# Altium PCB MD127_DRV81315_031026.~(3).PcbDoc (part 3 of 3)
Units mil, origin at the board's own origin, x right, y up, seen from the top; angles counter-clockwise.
Board outline 4400.04 x 2800.87 mil, 2 copper layers (Top Layer, Bottom Layer), stack 64.712 mil thick; 152 components, 62 nets, 376 pads, 751 vias.

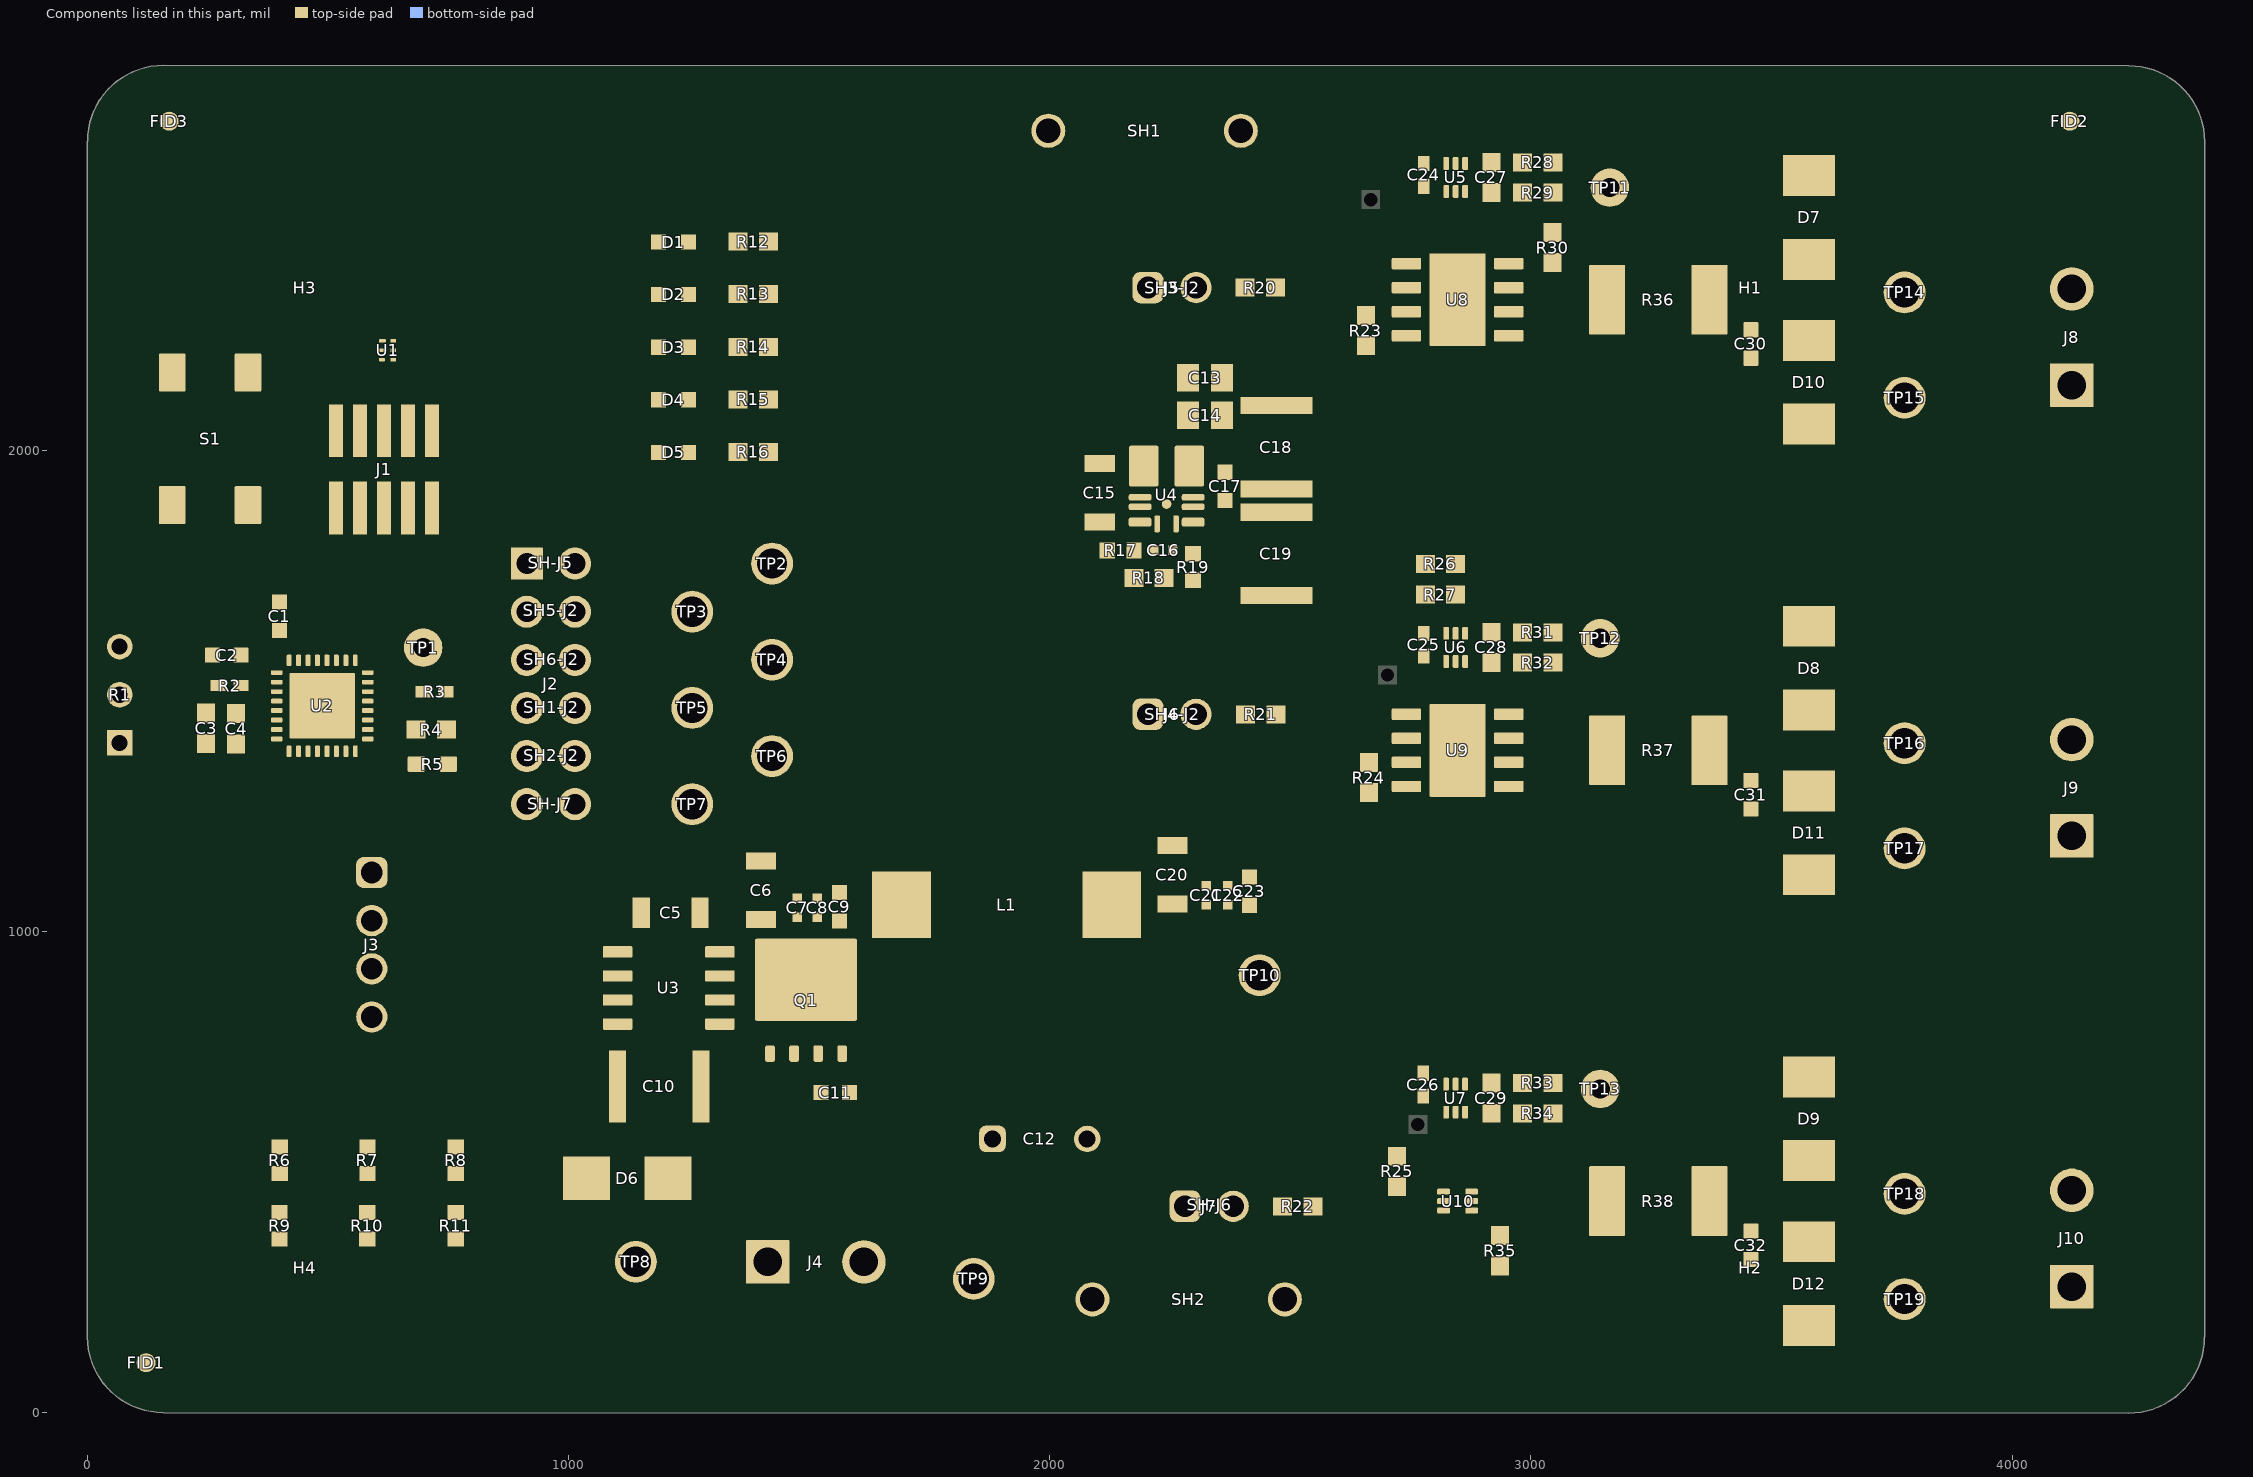
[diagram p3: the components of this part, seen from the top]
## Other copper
Top Layer:
  pour cut-out: 170.11,2634.3 cw(c170.11,2684.08) 120.32,2684.08 cw(c170.11,2684.08) 170.11,2733.87 cw(c170.11,2684.08) 219.9,2684.08 cw(c170.11,2684.08)
  pour cut-out: 122.11,54.3 cw(c122.11,104.08) 72.32,104.08 cw(c122.11,104.08) 122.11,153.87 cw(c122.11,104.08) 171.9,104.08 cw(c122.11,104.08)
  pour cut-out: 4120.11,2634.3 cw(c4120.11,2684.08) 4070.32,2684.08 cw(c4120.11,2684.08) 4120.11,2733.87 cw(c4120.11,2684.08) 4169.9,2684.08 cw(c4120.11,2684.08)
  region net NetU4_5: 2213.61,1895.61 2225.56,1907.57 2225.56,2006.35 2222.26,2009.65 2167.1,2009.65 2161.82,2004.36 2161.82,1900.07 2166.27,1895.61
  region net BUCK_3V3: 191.6,1488.81 191.6,1554.6 198.74,1561.74 225.19,1561.74 245.93,1541 269.57,1541 287.57,1522.99 287.57,1498.14 300.75,1484.96 404.82,1484.96 406.38,1483.4 406.38,1475.17 403.3,1472.09 375.98,1472.09 350.35,1446.47 350.35,1438.98 341.8,1430.43 323.99,1430.43 206.18,1430.43 191.6,1445.01
  region net 3V3: 1209.45,1973.16 1204.5,1968.21 1127.79,1968.21 1116.3,1980 1116.3,2221.3 1136.79,2241.79 1202.26,2241.79 1209.45,2234.6
  region net 3V3: 1200.21,2414.89 1129.11,2414.89 1125,2419 1125,2446 1128.79,2449.79 1200.91,2449.79 1202.26,2448.44 1202.26,2416.95
  region net 3V3: 2774,1603.79 2691.21,1603.79 2665,1630 2665,1705 2687.2,1727.2 2803.8,1727.2 2810.65,1720.35 2810.65,1653.58 2830.75,1633.48 2830.75,1605.74 2828.8,1603.79
  region net SRC_U3: 2993.19,436.65 2909.15,436.65 2894.05,451.76 2863.01,451.78 2860.51,454.29 2860.51,563.15 2868.36,571 2994,571 3017.91,594.91 3017.91,641.31 3034.61,658.01 3074.14,658.01 3094.77,678.63 3094.77,721.77 3112,739 3251,739 3277,713 3277,362.53 3274.14,359.67 3070.16,359.67
  region net BUCK_3V3: 631.06,2223.75 628.36,2226.45 628.36,2242.5 622,2248.86 622,2273 624,2275 643,2275 646.81,2271.19 646.81,2226.47 644.09,2223.75
  region net 3V3: 2769.71,2376.3 2771.71,2378.31 2771.71,2431.29 2766,2437 2713,2437 2708,2432 2708,2380.16 2711.87,2376.3
  region net nRST: 619.54,2218.89 584.68,2218.89 575.2,2209.41 556.98,2209.41 552.49,2213.9 552.49,2231.49 565.59,2244.58 580.44,2244.58 588.92,2236.1 619.48,2236.1 622.01,2233.57 622.01,2221.37
  region net BUCK_3V3: 776.53,530.78 386.49,530.78 371.96,545.32 371.96,585.47 379.85,593.36 771.22,593.36 788,576.58 788,542.24
  region net GND: 555.91,1403.12 553.88,1401.09 421.28,1401.09 420.09,1402.28 420.09,1439.89 407.36,1452.62 382.83,1452.62 380.85,1454.6 380.85,1464.28 381.7,1465.12 416.21,1465.12 420.09,1469 420.09,1535.72 421.28,1536.91 554.72,1536.91 555.91,1535.72
  region net VM: 2514,986.82 2514,868 2474,828 2136,828 2050,914 2050,1110.41 2082,1138.12 2238.88,1138.12 2306.71,1070.29 2430.53,1070.29
  region net BUCK_3V3: 2313.36,2033.58 2212.92,2033.58 2203.75,2042.74 2203.75,2169.99 2218.67,2184.91 2315.95,2184.91 2326.84,2174.02 2326.84,2046.68
  region net PI_IN: 1965,446 1946,427 1636,427 1620,443 1620,779 1603,796 1387,796 1376.88,806.12 1376.88,913.12 1353,937 1264,937 1227.61,973.39 1227.61,1077.61 1237,1087 1332,1087 1369.8,1049.2 1587.2,1049.2 1594,1056 1594,1121.25 1611.75,1139 1825,1139 1965,999
  region net GND: 2268.19,1863.04 2266.27,1864.96 2241.16,1864.96 2235.78,1859.59 2235.78,1832.56 2238.82,1829.53 2266.27,1829.53 2268.19,1831.45
  region net BUCK_3V3: 2239.68,1805.64 2238.99,1804.95 2238.99,1774.57 2218.01,1753.58 2218.01,1704.39 2235.71,1686.69 2305.88,1686.69 2317.24,1698.05 2317.24,1749.58 2315.62,1751.2 2285.72,1751.2 2269.54,1767.37 2269.54,1802.91 2266.81,1805.64
  region net VM_IN: 1490,322 1490,118 1453,81 1069,81 1037,113 1037,365 1144,472 1144,561 1181,598 1181,837.62 1134.62,884 1062,884 1058,888 1058,923 1066,931 1261.11,931 1267.2,924.91 1267.2,847.8 1286,829 1350,829 1358,821 1358,798 1373,783 1528,783 1547,764 1547,383 1491,327
  region net 3V3: 2802.28,426.07 2831.74,426.07 2833.87,423.94 2833.87,383.87 2832,382 2803,382 2801,384 2801,424.78
  region net 3V3: 2765.07,505.65 2774.79,515.36 2774.79,551.21 2765.89,560.11 2710.43,560.11 2701.93,551.61 2701.93,514.21 2710.5,505.65
  region net SRC_U1: 3025.97,2516.84 3025.97,2554.24 3034.47,2562.74 3074.14,2562.74 3116.4,2605 3176,2605 3203.2,2577.8 3203.2,2516.89 3186.26,2499.94 3042.87,2499.94
  region net 3V3: 2675.7,2237.19 2638.3,2237.19 2629.73,2228.62 2629.73,2148.27 2636,2142 2679,2142 2684.2,2147.2 2684.2,2228.69
  region net 3V3: 2807,2649 2748.21,2649 2740,2640.79 2740,2589.63 2749.21,2580.43 2828.8,2580.43 2830.75,2582.38 2830.75,2625.25
  region net OUT_U2: 3071.77,1239.98 3031.73,1280.02 2923.84,1280.02 2911.01,1291.34 2911.01,1479.89 2903.2,1487.7 2787.19,1487.7 2781.29,1481.8 2781.29,1029.71 2811,1000 3480.36,1000 3487.51,1007.15 3487.51,1165.51 3526.99,1204.99 3660.39,1204.99 3749.39,1294 4314,1294 4342.57,1322.57 4342.57,1495.87 4297.4,1541.04 3522.37,1541.04 3487.51,1506.18 3487.51,1300.14 3469.14,1281.77 3241.76,1281.76 3199.98,1239.98
  region net 3V3: 2680.43,1237.43 2690.2,1246.92 2690.2,1299.67 2681.7,1308.17 2644.3,1308.17 2635.73,1299.6 2635.73,1246.66 2644.96,1237.43
  region net 3V3: 2685,711.5 2712.48,684.02 2796.24,684.02 2814.22,667.16 2828.03,667.16 2830.47,669.6 2830.47,717.53 2807,741 2694,741 2685,732
  region net OUT_U3: 2985.97,427.67 3062.64,351 3475.68,351 3483.03,358.34 3483.03,571.54 3517.52,606.02 4303.98,606.02 4342.57,567.43 4342.57,384.57 4316.34,358.34 3757.91,358.34 3664.36,264.8 3532.86,264.8 3483.03,214.97 3483.03,110.03 3448,75 3027,75 2981,121 2981,312 2958,335 2875,335 2860.26,349.74 2860.26,426.11 2861.82,427.67
  region net SRC_U2: 2988.7,1320.96 2995.57,1314.1 2995.56,1289.74 2997.64,1287.66 3037.78,1287.66 3079.44,1246 3195,1246 3202.52,1253.52 3202.52,1351.62 3202.52,1657.48 3186,1674 3093,1674 3085,1666 3085,1596.97 3074.14,1586.11 3028.38,1586.11 3022.19,1579.92 3022.19,1524.94 3007.25,1510 2936,1510 2920.7,1494.7 2920.7,1332.27 2932.01,1320.96
  region net OUT_U1: 3488.34,2099.14 3488.34,1987.13 3461.09,1959.89 2943.11,1959.89 2918.94,1984.06 2918.94,2252.54 2923.48,2257.08 3050.92,2257.08 3084.38,2223.62 3475.47,2223.62 3485,2233.15 3485,2391 3475,2401 3098.76,2401 3063.73,2365.97 2930.7,2365.97 2921,2375.67 2921,2413 2926.01,2418.01 3061.56,2418.01 3133.55,2490 4301,2490 4342.57,2448.43 4342.57,2251.65 4323.92,2233 3755.24,2233 3666.24,2144 3533.2,2144
  region net VM: 3495.88,1971.82 3475.53,1951.47 2406.43,1951.47 2379.68,1924.71 2347.21,1924.71 2336.25,1913.75 2275.71,1913.75 2273.32,1911.36 2273.32,1875.53 2275.87,1872.98 2332.82,1872.98 2390.56,1815.24 4313.25,1815.25 4342.57,1844.57 4342.57,2199.15 4319.37,2222.36 3759.09,2222.36 3669.86,2133.12 3537.86,2133.12 3495.88,2091.15
  region net VM: 3495.88,1154.52 3537.86,1196.49 3669.86,1196.49 3759.09,1285.72 4319.37,1285.72 4342.57,1262.52 4342.57,1036.77 4307.3,1001.5 3506.5,1001.5 3495.88,1012.12
  region net VM: 3495.88,212.64 3536.81,253.56 3663.56,253.56 3759.09,349.09 4319.37,349.09 4342.57,325.89 4342.57,100.14 4307.3,64.87 3531.74,64.87 3495.88,100.73
  region net SRC_U1: 3092.26,2231 3057.26,2266 2923.6,2266 2917.8,2271.8 2917.8,2353.42 2923.44,2359.06 3073.26,2359.06 3109.2,2395 3193.87,2395 3202.52,2386.35 3202.52,2238.52 3195,2231
  text ".Layer_Name" at -36.39,-1858.41 h60
Bottom Layer:
  region net BUCK_3V3: 2285.36,2164.08 2285.36,2164.09 2304.21,2145.23 2304.21,2101.61 2289.7,2087.09 2148.34,2087.09 2128.37,2107.06 2128.37,2146.13 2146.33,2164.08
  text ".Layer_Name" at -36.39,-1858.41 h60

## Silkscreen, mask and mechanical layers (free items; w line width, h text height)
Top Overlay:
  lines w5: 634,1469.95 800.95,1470.01 800.95,1698 634,1698 634,1469.96 ; 745.3,1526.2 759.54,1544.38 ; 2237.45,2164.34 2246.45,2164.34 ; 2239.62,1810.27 2241.35,1812 2318,1812 2334,1796 2334,1778 ; 2241,2094 2258,2076 ; 2637,2498.31 2605.12,2498.31 2605.12,2718.85 3093,2718.85 3093,2498.31 2697,2498.31 ; 2672.31,1517 2637.34,1517 2637.34,1821.32 3082.16,1821.32 3082.16,1517 2730,1517 ; 2735.31,580 2712,580 2712,838.41 3082,838.41 3082,580 2794,580 ; 2818,2646 2832,2621 ; 2875,1641 2906,1760 ; 328,761.05 758.23,761.05 758.23,1185.63 328,1185.63 328,761.05 ; 561,2170 748.12,2170 748.12,2244 561,2244 561,2170 ; 642,1258 642,1455 832,1455 832,1258 642,1258
  lines w10: 545.95,2619.63 523.58,2642 ; 545.95,2664.37 523.58,2642 ; 779.95,2642 523.58,2642 ; 963.3,308 963.3,2712 ; 1066.25,1264.56 1077.99,1264.56 ; 1066.25,1364.56 1082,1364.56 ; 1066.25,1464.56 1081,1465 ; 1066.25,1564.56 1081.24,1564.56 ; 1066.25,1664.56 1081,1664.56 ; 1066.25,1764.56 1079,1764.56 ; 1155.37,2642 1413.08,2642 ; 1179.74,1364.56 1352.93,1364.56 ; 1181,1564.56 1352.93,1564.56 ; 1181.04,1764.56 1352.91,1764.56 ; 1327.04,1264.69 1380,1264.69 ; 1327.04,1464.69 1521,1464.69 ; 1327.04,1664.69 1521,1664.69 ; 1390.71,2619.63 1413.08,2642 ; 1390.71,2664.37 1413.08,2642 ; 1492.91,1364.69 1520,1364.69 ; 1492.91,1564.69 1520,1564.69 ; 1492.91,1764.69 1520,1764.69 ; 2281.7,2623.54 2335.7,2623.54 2335.7,2593.15 ; 2315.7,2593.15 2355.7,2593.15 ; 2326.7,2579.54 2345.7,2579.54 ; 2335.38,2566.46 2335.38,2568.05 ; 2368.71,183.06 2422.71,183.06 2422.71,152.67 ; 2402.71,152.67 2442.71,152.67 ; 2413.71,139.06 2432.71,139.06 ; 2422.39,125.98 2422.39,127.57 ; 249.15,292.11 858.23,292.11 858.23,604.39 249.15,604.39 249.15,292.11 ; 463.11,1799.19 849.49,1799.19 849.49,2147.73 463.11,2147.73 463.11,1799.19 ; 1093.24,1921.66 1093.24,2517 1579.1,2517 1579.1,1921.66 1093.24,1921.66 ; 2049.54,1653.86 2049.54,2200.24 2598.94,2200.24 2598.94,1653.86 2049.54,1653.86 ; 2615,173 2615,569.65 3090.34,569.65 3090.34,173 2615,173 ; 2615,1187 3090.34,1187 3090.34,1502.78 2615,1502.78 2615,1187 ; 2615,2110.11 2615,2489.7 3094.02,2489.7 3094.02,2110.11 2615,2110.11
  lines w30: 129,2454.08 ccw(c159,2454.08) 159,2424.08 760.68,2424.08 ccw(c760.68,2454.08) 790.68,2454.08 790.68,2552 ccw(c760.68,2552) 760.68,2582 159,2582 ccw(c159,2552) 129,2552 129,2454.08
  text "CSA 1" at 2766.9,2722.73 h60
  text "DRV81315-Q1" at 1128.49,2695.25 h118.11
  text "MSPM0" at 439,2690 h118.11
  text "TVS" at 3528,2636 h30
  text "GND" at 1885,2538.28 h106.3
  text "LED STATUS" at 1124.53,2527 h60
  text "3V3_STATUS" at 1249.05,2463.51 h30
  text "OUT_U1" at 3668.69,2452.88 h70
  text "OUT_U1" at 3977,2448 h80
  text "DRV81315-Q1 EVM" at 131.75,2430.66 h95
  text "SRC_U1" at 3112,2392 h65
  text "MCU_STATUS" at 1249.05,2353.2 h30
  text "MD127E1" at 259,2329 h108.27
  text "RECIRC" at 3500,2284 h30
  text "ESD PROTECTION" at 478.53,2247.78 h45
  text "STATUS_U8" at 1249.05,2239.62 h30
  text "DRV81315ADDA" at 2628.4,2130.65 h40
  text "STATUS_U9" at 1249.05,2129.59 h30
  text "STATUS_U10" at 1252.38,2019.59 h30
  text "VM" at 3733,1918 h80
  text "CSA 2" at 2759.9,1826.73 h60
  text "10-PIN ARM CONNECTOR" at 321.18,1749 h45
  text "3V3" at 1527,1736 h70
  text "TVS" at 3528,1699.37 h30
  text "0%" at 97.86,1667.22 h35
  text "BUCK 3V3 SUPPLY" at 2041.42,1649.8 h70 r90
  text "IN" at 1527,1636 h70
  text "STATUS_U8" at 1526.64,1526.4 h70
  text "OUT_U2" at 3974.94,1520.59 h80
  text "OUT_U2" at 3664.07,1518.44 h70
  text "BSL INVOKE" at 852.42,1467 h45 r90
  text "SRC_U2" at 3124.78,1455.08 h65
  text "STATUS_U9" at 1527,1426.4 h70
  text "RECIRC" at 3504.98,1353.94 h30
  text "STATUS_U10" at 1514.85,1326.53 h70
  text "100%" at 76.48,1275.12 h35
  text "GND" at 1385.89,1221 h70
  text "DRV81315DDA" at 2642.04,1207.58 h40
  text "VM MONITORING" at 552,1199.88 h45
  text "PA24" at 391.79,1094 h59.06
  text "PA17" at 393.48,992 h59.06
  text "VM" at 3713,981.34 h80
  text "PA11" at 392.06,890.14 h59.06
  text "CSA 3" at 2794.9,843.73 h60
  text "PA1" at 419.74,793.23 h59.06
  text "TVS" at 3528,762.74 h30
  text "AUXILARY MCU PINS" at 319.66,700.8 h55
  text "DEVICE ID" at 247.4,610.69 h60
  text "OUT_U3" at 3678.09,584.63 h70
  text "OUT_U3" at 3974.5,583.67 h80
  text "SRC_U3" at 3112.19,519.16 h65
  text "RECIRC" at 3507,415 h30
  text "DEV_ID1" at 335.22,340.79 h59.06 r90
  text "DEV_ID3" at 697.1,340.26 h59.06 r90
  text "DEV_ID2" at 517.06,338.72 h59.06 r90
  text "6V TO 18V" at 670.59,211.43 h90
  text "DRV81315ADRL" at 2625.9,187.62 h40
  text "GND" at 2138,115.28 h106.3
  text "VM" at 1023.93,78.3 h137.8
  text "GND" at 1740,73 h137.8
  text "VM" at 3724.88,44.86 h80
  text ".Layer_Name" at 291.58,-1858.41 h60
Bottom Overlay:
  lines w10: 106.54,1392.67 160.28,1393.45 ; 106.54,1492.67 160.28,1493.45 ; 106.54,1592.67 160.28,1593.45 ; 1066.25,1264.56 1187.04,1264.56 ; 1066.25,1364.56 1352.93,1364.56 ; 1066.25,1464.56 1187.04,1464.56 ; 1066.25,1564.56 1352.93,1564.56 ; 1066.25,1664.56 1187.08,1664.56 ; 1066.25,1764.56 1352.91,1764.56 ; 1308.33,1264.69 1358.33,1264.69 ; 1308.33,1464.69 1358.33,1464.69 ; 1308.33,1664.69 1358.33,1664.69 ; 1474.21,1364.69 1524.21,1364.69 ; 1474.21,1564.69 1524.21,1564.69 ; 1479.02,1764.69 1517.61,1764.69 ; 2119.84,1451.48 2163.66,1451.48 ; 2119.84,2338.11 2163.66,2338.11 ; 2197,429 2240.83,429
  text "SRC_U1" at 3246.06,2605 h65
  text "OUT_U1" at 3918.59,2413.24 h70
  text "OUT_U1" at 4279,2403 h80
  text "IN" at 2102,2299 h80
  text "VM" at 4172.47,1963 h80
  text "VM" at 3831,1959 h80
  text "3V3" at 1735,1737 h70
  text "SRC_U2" at 3246.06,1670 h65
  text "IN" at 1582.5,1624.64 h70
  text "GND" at 412.28,1556.36 h80
  text "STATUS_U8" at 1882.36,1518.4 h70
  text "OUT_U2" at 3904.3,1475.87 h70
  text "OUT_U2" at 4271.57,1473.14 h80
  text "POT_IN" at 448.3,1451.07 h80
  text "STATUS_U9" at 1717.9,1419.84 h70
  text "IN" at 2102,1412.37 h80
  text "BUCK_3V3" at 485.97,1351.07 h80
  text "STATUS_U10" at 1878.21,1320.59 h70
  text "GND" at 1529.55,1228.42 h70
  text "VM" at 3835,1016 h80
  text "VM" at 4181,1016 h80
  text "SRC_U3" at 3245,724 h65
  text "OUT_U3" at 4293,536 h80
  text "OUT_U3" at 3903.91,531.63 h70
  text "IN" at 2179.16,389.89 h80
  text "VM" at 3839.81,91.68 h80
  text "VM" at 4187.47,91.68 h80
  text "VM" at 1216,78 h137.8
  text "GND" at 1979,74 h137.8
  text ".Layer_Name" at -36.39,-1858.41 h60
Top Paste:
  text ".Layer_Name" at -36.39,-1858.41 h60
Bottom Paste:
  text ".Layer_Name" at -36.39,-1858.41 h60
Top Solder:
  text ".Layer_Name" at -36.39,-1858.41 h60
  text ".Layer_Name" at -36.39,-1858.41 h60
Bottom Solder:
  text ".Layer_Name" at -36.39,-1858.41 h60
Drill Guide:
  text ".Layer_Name" at -36.39,-1858.41 h60
M1 Board Outline:
  lines w10: 0,2642.49 -0.04,157.84 ccw(c157.47,157.84) 157.47,0.36 ; 0.37,2642.49 cw(c157.85,2642.49) 157.85,2799.97 4242.57,2799.1 ; 157.49,-0.03 4242.52,-0.9 ; 4242.11,-0.9 ccw(c4242.11,156.58) 4399.59,156.58 ; 4242.52,2799.04 cw(c4242.52,2641.56) 4400,2641.56 4400,156.58
  text ".Layer_Name" at -36.39,-1858.41 h60
M2 Board Dimensions:
  rectangle: -613.39,-1274.91 -488.39,-1149.91
  rectangle: -488.39,-1399.91 -113.39,-1274.91
  lines w7: -613.39,-1274.91 386.61,-1274.91 ; -488.39,-1399.91 -488.39,-1149.91 ; -363.39,-1399.91 -363.39,-1149.91 ; -113.39,-1399.91 -113.39,-1149.91 ; 136.61,-1399.91 136.61,-1149.91 ; -613.39,-1399.91 386.61,-1399.91 386.61,-1149.91 -613.39,-1149.91 -613.39,-1399.91
  text ".Layer_Name" at -36.39,-1858.41 h60
M3 3D STEP Top:
  text ".Layer_Name" at -36.39,-1858.41 h60
M4 3D STEP Bottom:
  text ".Layer_Name" at -36.39,-1858.41 h60
M5 Assembly Top:
  lines w10: -905.39,-1930.08 5694.61,-1930.08 ; -905.39,-1726.75 5696.61,-1726.75 ; -905.39,-1523.41 -905.39,-2133.41 3099.61,-2133.41 5696.61,-2133.41 5696.61,-1523.41 -904.89,-1523.41 -904.89,-2133.41 670.61,-2133.41 ; 1559.61,-2133.41 1559.61,-1523.41 ; 2826.61,-1726.75 2826.61,-1523.41 ; 3666.61,-1726.75 3666.61,-1523.41 ; 4288.61,-2139.91 4288.61,-1937.08
  text "COMPONENTS MARKED 'DNP' SHOULD NOT BE POPULATED." at 540.11,-1318.41 h60
  text "ASSEMBLY VARIANT:" at 539.61,-1433.91 h60
  text ".VariantName" at 1575.61,-1433.91 h60
  text "PCB VIEWED FROM TOP SIDE" at -841.89,-1655.58 h60
  text "BOARD #:" at 1634.61,-1655.58 h60
  text ".PRJ_Number" at 2180.11,-1655.58 h60
  text "REV:" at 3024.61,-1655.58 h60
  text ".PCB_Rev" at 3316.11,-1655.58 h60
  text "SVN REV:" at 3862.61,-1655.58 h60
  text ".VersionControl_RevNumber" at 4368.61,-1655.58 h60
  text "TID #:" at 1634.61,-1858.91 h60
  text ".TID" at 2180.11,-1858.91 h60
  text "PLOT NAME =" at -841.89,-2064.25 h60
  text ".plot_File_Name" at -36.39,-2064.25 h60
  text "GENERATED    :" at 1636.61,-2064.25 h60
  text ".Print_Date" at 2506.11,-2064.25 h60
  text ".Print_Time" at 3235.11,-2064.25 h60
  text "TEXAS INSTRUMENTS" at 4499.61,-2064.25 h60
M6 Assembly Bottom:
  lines w10: -905.89,-1727.25 5696.11,-1727.25 ; -903.89,-1930.58 5696.11,-1930.58 ; 502.11,-2140.41 502.11,-1937.58 ; 1124.11,-1727.25 1124.11,-1523.91 ; 1964.11,-1727.25 1964.11,-1523.91 ; 3231.11,-2133.91 3231.11,-1523.91 ; 4120.11,-2133.91 5695.61,-2133.91 5695.61,-1523.91 -905.89,-1523.91 -905.89,-2133.91 1691.11,-2133.91 5696.11,-2133.91 5696.11,-1523.91
  text "COMPONENTS MARKED 'DNP' SHOULD NOT BE POPULATED." at 5488.61,-1317.91 h60
  text ".VersionControl_RevNumber" at 9967,-1372.91 h60
  text ".VariantName" at 4444.61,-1433.91 h60
  text "ASSEMBLY VARIANT:" at 5483.61,-1433.91 h60
  text "SVN REV:" at 928.11,-1656.08 h60
  text ".PCB_Rev" at 1474.61,-1656.08 h60
  text "REV:" at 1766.11,-1656.08 h60
  text ".PRJ_Number" at 2610.61,-1656.08 h60
  text "BOARD #:" at 3156.11,-1656.08 h60
  text "PCB VIEWED FROM BOTTOM SIDE" at 5632.61,-1656.08 h60
  text ".TID" at 2610.61,-1859.41 h60
  text "TID #:" at 3156.11,-1859.41 h60
  text "TEXAS INSTRUMENTS" at 291.11,-2064.75 h60
  text ".Print_Time" at 1555.61,-2064.75 h60
  text ".Print_Date" at 2284.61,-2064.75 h60
  text "GENERATED    :" at 3154.11,-2064.75 h60
  text ".plot_File_Name" at 4827.11,-2064.75 h60
  text "PLOT NAME =" at 5632.61,-2064.75 h60
M9 Title Sheet:
  drawing of 57 lines, arcs and shapes, not listed
  text "1" at 126.45,7036.59 h70
  text "2" at 2622.11,7036.59 h70
  text "3" at 5111.46,7036.59 h70
  text "4" at 7618.13,7036.59 h70
  text "5" at 10117.11,7036.59 h70
  text "6" at 12622.11,7036.59 h70
  text "A" at -1029.89,5893.59 h70
  text "A" at 13770.11,5893.59 h70
  text "B" at -1029.89,3513.59 h70
  text "B" at 13770.11,3513.59 h70
  text "C" at -1029.89,1138.59 h70
  text "C" at 13770.11,1138.59 h70
  text "PROJECT TITLE:" at 10730.11,-722.41 h45
  text ".PRJ_Title" at 10780.11,-855.74 h70
  text "DESIGNED FOR:" at 10730.11,-1023.41 h45
  text ".PRJ_Customer" at 10780.11,-1163.41 h70
  text "D" at -1029.89,-1231.41 h70
  text "D" at 13770.11,-1231.41 h70
  text "FILE NAME:" at 10730.11,-1323.41 h45
  text ".PCB_File_Name_No_Path" at 10780.11,-1443.41 h70
  text "Texas Instruments (TI) and/or its licensors do not warrant the accuracy or completeness of this specification" at 5760.61,-1605.25 h45
  text "ENGINEER:" at 10730.11,-1613.41 h45
  text "LAYOUT BY:" at 12235.11,-1613.41 h45
  text "or any information contained therein. TI and/or its licensors do not warrant that this design will meet" at 5715.63,-1717.92 h45
  text ".PRJ_Engineer" at 10780.11,-1768.41 h70
  text "PACTRON" at 12285.61,-1768.41 h70
  text "the specifications, will be suitable for your application or fit for any particular purpose, or will operate in" at 5715.63,-1830.58 h45
  text ".Layer_Name" at -36.39,-1858.41 h60
  text "ALTIUM DESIGNER VERSION:" at 12235.11,-1923.41 h45
  text "an implementation. TI and/or its licensors do not warrant that the design is production worthy. You should" at 5715.63,-1943.25 h45
  text "completely validate and test your design implementation to confirm the system functionality for your application." at 5760.61,-2055.91 h45
  text ".print_Scale" at 10780.11,-2056.74 h70
  text ".Application_BuildNumber" at 12285.61,-2056.74 h70
  text "1" at 126.45,-2263.41 h70
  text "2" at 2622.11,-2263.41 h70
  text "3" at 5111.46,-2263.41 h70
  text "4" at 7618.13,-2263.41 h70
  text "5" at 10117.11,-2263.41 h70
  text "6" at 12622.11,-2263.41 h70
M10 Fab Notes:
  drawing of 189 lines, arcs and shapes, not listed
  text "FAB NOTE:" at -479.61,6724.26 h120
  text "1.NO VENDOR LOGO OR NAME ON THE BOARD" at -484.61,6550.09 h100
  text "2.ALL HOLES SHOULD BE FHS." at -484.61,6375.92 h100
  text "3.CLIP SILKSCREEN ON NO MASK AREA." at -484.61,6201.75 h100
  text "4.VIA PLUGGING:YES,ALL 7.87 , 8 MIL DRILLS ARE NEED TO BE SOLDER MASK OR NON-CONDUCTIVE VIA PLUGGING FROM COMPONENT BOTTOM SIDE." at -484.61,6017.42 h100
  text "5.TAIYO INK - GREEN MATTE NEED TO BE FOLLOWED" at -484.61,5822.5 h100
  text "DESIGN INFORMATION" at 11768.63,5356.26 h60
  text "MIN. TRACK WIDTH:" at 11124.07,5224.13 h60
  text "10" at 12220.32,5224.14 h60
  text "MIL" at 12375.07,5224.13 h60
  text "6" at 12225.94,5102.45 h60
  text "MIN. CLEARANCE:" at 11124.07,5100.01 h60
  text "MIL" at 12375.07,5100.01 h60
  text "MIN. VIA PAD SIZE:" at 11124.07,4975.88 h60
  text "MIL" at 12375.07,4975.88 h60
  text "14" at 12189.33,4972.89 h60
  text "0.05mm (2MIL)" at 11819.07,4845.98 h60
  text "MINIMUM ANNULAR RING" at 10794.84,4837.76 h60
  text "EXTERNAL" at 12527.07,4837.76 h60
  text "PER" at 10994.84,4727.63 h60
  text "IPC-D-275 CLASS 2 LEVEL C" at 11214.84,4727.63 h60
  text "MIL, HOLES" at 12703.07,4627.15 h60
  text "+/-" at 12310.61,4618.57 h60
  text "+/-" at 13164.61,4618.57 h60
  text "REGISTRATION TOLERANCES:" at 10794.84,4617.5 h60
  text "METAL" at 11994.61,4617.5 h60
  text "5" at 12570.82,4617.51 h60
  text "3" at 13403.82,4617.51 h60
  text "MIL" at 13520.07,4617.5 h60
  text "HOLE SIZE TOLERANCE (UNLESS OTHERWISE SPECIFIED):" at 10794.84,4519.19 h60
  text "+/-" at 13164.61,4516.32 h60
  text "3" at 13403.82,4515.26 h60
  text "MIL" at 13520.07,4515.25 h60
  text "MATERIAL:" at 10720.07,4377.61 h60
  text "FR-4 High Tg" at 11706.52,4249.08 h60
  text "X" at 11562.08,4241.09 h60
  text "FR-4" at 11141.08,4236.57 h60
  text "OTHER" at 12629.07,4236.57 h60
  text "62 MIL (1.6mm) +/-10%" at 11461.18,4093.55 h60
  text "X" at 11341.08,4091.09 h60
  text "THICKNESS:" at 10794.84,4085.32 h60
  text "OTHER" at 12746.07,4085.32 h60
  text "TOLERANCE:" at 10794.84,3947.01 h60
  text "X" at 11643.08,3947.01 h60
  text "ANSI IPC-6012 TYPE 3 CLASS 2" at 11821.09,3947.01 h60
  text "OTHER +/-" at 11821.07,3802.82 h60
  text "BOW & TWIST:" at 10794.84,3657.63 h60
  text "X" at 11643.08,3657.63 h60
  text "ANSI IPC-6012 TYPE 3 CLASS 2" at 11821.09,3657.63 h60
  text "OTHER +/-" at 11821.07,3510.93 h60
  text "DRILLING:" at 10720.07,3380.32 h60
  text "NC_DRILL FILES" at 12481.07,3275.13 h60
  text "REFERENCE:" at 10794.84,3271.19 h60
  text "X" at 11452.08,3271.09 h60
  text "AS SHOWN" at 11630.07,3271.19 h60
  text "X" at 12353.08,3271.19 h60
  text "OTHER" at 12779.07,3128.94 h60
  text "PTH COPPER THICKNESS:" at 10794.52,3125.41 h60
  text "X" at 11933.76,3125.41 h60
  text "20-30 um" at 12061.75,3125.41 h60
  text "BOARD FINISH:" at 10720.07,2977.81 h60
  text "SILKSCREEN:" at 10875.3,2867.69 h60
  text "X" at 11833.08,2867.69 h60
  text "TOP" at 11950.07,2867.69 h60
  text "X" at 12343.08,2867.69 h60
  text "BOTTOM" at 12461.07,2867.69 h60
  text "SILKSCREEN COLOR:" at 10875.3,2712.5 h60
  text "X" at 11832.08,2712.5 h60
  text "WHITE" at 11950.07,2712.5 h60
  text "OTHER" at 12461.07,2712.5 h60
  text "X" at 11963.08,2569.05 h60
  text "GREEN" at 12081.07,2569.05 h60
  text "OTHER" at 12699.07,2569.05 h60
  text "SOLDER RESIST COLOR:" at 10875.3,2562.18 h60
  text "X" at 11963.08,2414.8 h60
  text "MATTE" at 12081.07,2414.8 h60
  text "SEMI-GLOSS" at 12698.61,2414.16 h60
  text "IMMERSION GOLD (ENIG)" at 11781.07,2242.02 h60
  text "ENEPIG" at 13118.61,2234.8 h60
  text "SURFACE FINISH:" at 10720.07,2233.8 h60
  text "X" at 11603.08,2233.8 h60
  text "IMM. TIN/SILVER OR EQUIV" at 11049.61,2096.49 h60
  text "OTHER" at 12481.07,2092.55 h60
  text "ARRAY/PANEL:" at 10720.07,1937.17 h60
  text "X" at 11603.08,1932.98 h60
  text "CUT AND TRIM PER M1 BOARD OUTLINE" at 11781.07,1928.95 h60
  text "N.C. ROUTE" at 11781.07,1792.98 h60
  text "V. SCORE" at 12647.07,1792.98 h60
  text "CERTIFICATION:" at 10720.07,1663.86 h60
  text "MATERIALS AND WORKMANSHIP FOR ALL PCBS" at 11445.07,1663.86 h60
  text "TO MEET OR EXCEED THE REQUIREMENTS OF:" at 11445.07,1569.8 h60
  text "X" at 11082.58,1441.17 h60
  text "ANSI IPC-A-600F CLASS ->" at 11210.58,1441.17 h60
  text "X" at 12858.58,1441.17 h60
  text "2" at 12968.58,1441.17 h60
  text "1" at 12653.58,1439.67 h60
  text "3" at 13322.58,1439.67 h60
  text "X" at 11894.58,1293.48 h60
  text "RoHS" at 12022.58,1293.48 h60
  text "OTHER" at 12666.98,1293.48 h60
  text "PER ORDER" at 13064.04,1293.48 h60
  text "ALL BOARDS MUST MEET OR EXCEED UL94-V0 REQUIREMENTS." at 10747.61,1139.65 h60
  text "PCB MUST BEAR THE UL94V-0 UL REGISTERED MATERIAL ID NUMBER" at 10747.61,1023.59 h60
  text "ADDITIONAL REQUIREMENTS:" at 10720.07,854.17 h60
  text "MICROSECTION:" at 10794.84,747.04 h60
  text "YES" at 11700.58,747.04 h60
  text "REQUIRED" at 12562.07,602.71 h60
  text "BARE BOARD ELEC. TEST:" at 10794.84,599.85 h60
  text "NONE" at 12100.58,599.85 h60
  text "X" at 12444.08,599.85 h60
  text "PER ORDER" at 13154.07,599.85 h60
  text "XX MIL VIAS REQUIRE NON-CONDUCTIVE FILL AND PLANARIZE" at 10962.99,394.9 h59
  text "XX MIL VIAS REQUIRE CONDUCTIVE FILL AND PLANARIZE" at 10970.99,290.93 h60
  text "OUTER XX MIL TRACES REQUIRE 50 OHM SINGLE-ENDED IMPEDANCE" at 10970.01,127.54 h55
  text "LAYER 2 & 3 (INNER LAYERS) XX MIL WIDE, XX MIL SPACE / TRACES REQUIRE 100 OHM DIFFERENTIAL IMPEDANCE" at 10962.01,-108.17 h60
  text ".Layer_Name" at -36.39,-1858.41 h60
M11 Gerber Information:
  circle w10: c4400,-267.1 r100
  circle w10: c4400,-267.1 r50
  circle w10: c4400,3098.2 r100
  circle w10: c4400,3098.2 r50
  circle w10: c0,3098.2 r100
  circle w10: c0,3098.2 r50
  lines w10: -905.39,-1930.08 5694.61,-1930.08 ; -905.39,-1726.75 5696.61,-1726.75 ; -905.39,-1523.41 -905.39,-2133.41 3099.61,-2133.41 5696.61,-2133.41 5696.61,-1523.41 -904.89,-1523.41 -904.89,-2133.41 670.61,-2133.41 ; -150,3098.2 150,3098.2 ; 0,2948.2 0,3248.2 ; 1559.61,-2133.41 1559.61,-1523.41 ; 3126.61,-1726.75 3126.61,-1523.41 ; 3666.61,-1726.75 3666.61,-1523.41 ; 4250,-267.1 4550,-267.1 ; 4250,3098.2 4550,3098.2 ; 4288.61,-2139.91 4288.61,-1937.08 ; 4400,-417.1 4400,-117.1 ; 4400,2948.2 4400,3248.2
  text "ALL ARTWORK VIEWED FROM TOP SIDE" at -841.89,-1655.58 h60
  text "BOARD #:" at 1634.61,-1655.58 h60
  text "MD127_DRV81315" at 2180.11,-1655.58 h60
  text "REV:" at 3204.61,-1655.58 h60
  text "E1" at 3496.11,-1655.58 h60
  text "SVN REV:" at 3862.61,-1655.58 h60
  text ".VersionControl_RevNumber" at 4368.61,-1655.58 h60
  text "LAYER NAME =" at -841.89,-1858.41 h60
  text "TID #:" at 1634.61,-1858.91 h60
  text ".TID" at 2180.11,-1858.91 h60
  text ".plot_File_Name" at -165.39,-2047.25 h35
  text "PLOT NAME =" at -841.89,-2064.25 h60
  text "GENERATED    :" at 1636.61,-2064.25 h60
  text ".Print_Date" at 2506.11,-2064.25 h60
  text ".Print_Time" at 3235.11,-2064.25 h60
  text "TEXAS INSTRUMENTS" at 4499.61,-2064.25 h60
M12 Stackup:
  lines w10: 2874.7,4531.36 3069.7,4531.36 ; 2875.72,4769.91 3070.72,4769.91 ; 3024.7,4486.36 3069.7,4531.36 ; 3025.72,4724.91 3070.72,4769.91 ; 3026.28,4574.78 3069.7,4531.36 ; 3027.31,4813.32 3070.72,4769.91
  lines w15: -544.42,4354.09 -134.51,4354.09 795.23,4354.09 1655,4354.09 2304.84,4354.09 2874.7,4354.09 ; -544.42,4474.09 -134.51,4474.09 795.23,4474.09 1655,4474.09 2304.84,4474.09 2874.7,4474.09 ; -544.42,4594.09 -134.51,4594.09 795.23,4594.09 1655,4594.09 2304.84,4594.09 2874.7,4594.09 ; -544.42,4714.09 -134.51,4714.09 795.23,4714.09 1655,4714.09 2304.84,4714.09 2874.7,4714.09 ; -544.42,4834.09 -134.51,4834.09 795.23,4834.09 1655,4834.09 2304.84,4834.09 2874.7,4834.09 ; -544.42,4954.09 -134.51,4954.09 795.23,4954.09 1655,4954.09 2304.84,4954.09 2874.7,4954.09 ; -544.42,5074.09 2874.7,5074.09 ; -134.51,5194.09 -134.51,4234.09 ; 795.23,5194.09 795.23,4234.09 ; 1655,5194.09 1655,4234.09 ; 2304.84,5194.09 2304.84,4234.09 ; -134.51,4234.09 -544.42,4234.09 -544.42,5194.09 2874.7,5194.09 2874.7,4234.09 2304.84,4234.09 ; -134.51,4234.09 795.23,4234.09 ; 795.23,4234.09 1655,4234.09 ; 1655,4234.09 2304.84,4234.09
  text "STACK UP:" at -519.07,5234.76 h120
  text "Layer" at -474.42,5104.09 h60
  text "Name" at -64.51,5104.09 h60
  text "Material" at 865.23,5104.09 h60
  text "Thickness" at 1725,5104.09 h60
  text "Constant" at 2374.84,5104.09 h60
  text "Top Overlay" at -64.51,4984.09 h60
  text "Top Solder" at -64.51,4864.09 h60
  text "Solder Resist" at 865.23,4864.09 h60
  text "0.40mil" at 1725,4864.09 h60
  text "3.5" at 2374.84,4864.09 h60
  text "1" at -474.42,4744.09 h60
  text "Top Layer" at -64.51,4744.09 h60
  text "COPPER" at 865.23,4744.09 h60
  text "2.76mil" at 1725,4744.09 h60
  text "20Z (Copper + Plating)" at 3135.89,4733.32 h60
  text "Dielectric1" at -64.51,4624.09 h60
  text "FR-4 High Tg" at 865.23,4624.09 h60
  text "59.20mil" at 1725,4624.09 h60
  text "4.8" at 2374.84,4624.09 h60
  text "2" at -474.42,4504.09 h60
  text "Bottom Layer" at -64.51,4504.09 h60
  text "COPPER" at 865.23,4504.09 h60
  text "2.76mil" at 1725,4504.09 h60
  text "20Z (Copper + Plating)" at 3134.86,4494.78 h60
  text "Bottom Solder" at -64.51,4384.09 h60
  text "Solder Resist" at 865.23,4384.09 h60
  text "0.40mil" at 1725,4384.09 h60
  text "3.5" at 2374.84,4384.09 h60
  text "Bottom Overlay" at -64.51,4264.09 h60
  text "Total board thickness:" at -474.42,4144.09 h60
  text "65.51mil" at 1725,4144.09 h60
  text ".Layer_Name" at -36.39,-1858.41 h60
M13 Component Bodies Top:
  text ".Layer_Name" at -36.39,-1858.41 h60
M14 Component Bodies Bottom:
  text ".Layer_Name" at -36.39,-1858.41 h60
M15 Courtyards Top:
  text ".Layer_Name" at -36.39,-1858.41 h60
M16 Courtyards Bottom:
  text ".Layer_Name" at -36.39,-1858.41 h60
Drill Drawing:
  circle w10: c4602.57,5004.15 r33.33
  circle w10: c4602.57,3804.15 r20
  circle w10: c4602.57,3804.15 r33.33
  lines w10: 4569.24,3470.82 4602.57,3487.48 4635.91,3470.82 4619.24,3504.15 4635.91,3537.48 4602.57,3520.82 4569.24,3537.48 4585.91,3504.15 4569.24,3470.82 ; 4569.24,3637.48 4585.91,3637.48 4585.91,3620.82 4619.24,3620.82 4619.24,3637.48 4635.91,3637.48 4635.91,3670.82 4619.24,3670.82 4619.24,3687.48 4585.91,3687.48 4585.91,3670.82 4569.24,3670.82 4569.24,3637.48 ; 4569.24,3920.82 4569.24,3937.48 4585.91,3954.15 4569.24,3970.82 4569.24,3987.48 4585.91,3987.48 4602.57,3970.82 4619.24,3987.48 4635.91,3987.48 4635.91,3970.82 4619.24,3954.15 4635.91,3937.48 4635.91,3920.82 4619.24,3920.82 4602.57,3937.48 4585.91,3920.82 4569.24,3920.82 ; 4569.24,4220.82 4635.91,4220.82 4635.91,4287.48 4569.24,4287.48 4569.24,4220.82 ; 4569.24,4437.48 4635.91,4437.48 4602.57,4370.82 4569.24,4437.48 ; 4569.24,4587.48 4635.91,4587.48 4602.57,4520.82 4569.24,4587.48 ; 4569.24,4687.48 4585.91,4687.48 4585.91,4670.82 4619.24,4670.82 4619.24,4687.48 4635.91,4687.48 4635.91,4720.82 4619.24,4720.82 4619.24,4737.48 4585.91,4737.48 4585.91,4720.82 4569.24,4720.82 4569.24,4687.48 ; 4569.24,4820.82 4602.57,4837.48 4635.91,4820.82 4619.24,4854.15 4635.91,4887.48 4602.57,4870.82 4569.24,4887.48 4585.91,4854.15 4569.24,4820.82 ; 4569.24,5137.48 4585.91,5137.48 4602.57,5120.82 4619.24,5137.48 4635.91,5137.48 4619.24,5154.15 4635.91,5170.82 4619.24,5170.82 4602.57,5187.48 4585.91,5170.82 4569.24,5170.82 4585.91,5154.15 4569.24,5137.48 ; 4582.57,3484.15 4602.57,3494.15 4622.57,3484.15 4612.57,3504.15 4622.57,3524.15 4602.57,3514.15 4582.57,3524.15 4592.57,3504.15 4582.57,3484.15 ; 4582.57,3644.15 4592.57,3644.15 4592.57,3634.15 4612.57,3634.15 4612.57,3644.15 4622.57,3644.15 4622.57,3664.15 4612.57,3664.15 4612.57,3674.15 4592.57,3674.15 4592.57,3664.15 4582.57,3664.15 4582.57,3644.15 ; 4582.57,4424.15 4622.57,4424.15 4602.57,4384.15 4582.57,4424.15
  lines w15: 4509.45,3425.82 10615.77,3425.82 ; 4509.45,5225.82 10615.77,5225.82 ; 5060.32,3275.82 5060.32,5375.82 ; 5650.17,3275.82 5650.17,5375.82 ; 6749.85,3275.82 6749.85,5375.82 ; 7255.72,3275.82 7255.72,5375.82 ; 7989.53,3275.82 7989.53,5375.82 ; 9489.08,3275.82 9489.08,5375.82 ; 4509.45,3275.82 10615.77,3275.82 10615.77,5375.82 4509.45,5375.82 4509.45,3275.82
  text "DRILL TABLE:" at 4592,5473 h120
  text "Symbol" at 4599.45,5270.82 h72
  text "Count" at 5105.32,5270.82 h72
  text "Hole Size" at 5695.17,5270.82 h72
  text "Plated" at 6794.85,5270.82 h72
  text "Hole Type" at 7300.72,5270.82 h72
  text "Drill Layer Pair" at 8034.53,5270.82 h72
  text "Hole Tolerance" at 9534.08,5270.82 h72
  text "29" at 5105.32,5120.82 h60
  text "7.87mil (0.200mm)" at 5695.17,5120.82 h60
  text "PTH" at 6794.85,5120.82 h60
  text "Round" at 7300.72,5120.82 h60
  text "Top Layer - Bottom Layer" at 8034.53,5120.82 h60
  text "-3mil / +3mil" at 9534.08,5120.82 h60
  text "4" at 5105.32,4970.82 h60
  text "8.00mil (0.203mm)" at 5695.17,4970.82 h60
  text "PTH" at 6794.85,4970.82 h60
  text "Round" at 7300.72,4970.82 h60
  text "Top Layer - Bottom Layer" at 8034.53,4970.82 h60
  text "-3mil / +3mil" at 9534.08,4970.82 h60
  text "718" at 5105.32,4820.82 h60
  text "10.00mil (0.254mm)" at 5695.17,4820.82 h60
  text "PTH" at 6794.85,4820.82 h60
  text "Round" at 7300.72,4820.82 h60
  text "Top Layer - Bottom Layer" at 8034.53,4820.82 h60
  text "-3mil / +3mil" at 9534.08,4820.82 h60
  text "3" at 5105.32,4670.82 h60
  text "27.56mil (0.700mm)" at 5695.17,4670.82 h60
  text "PTH" at 6794.85,4670.82 h60
  text "Round" at 7300.72,4670.82 h60
  text "Top Layer - Bottom Layer" at 8034.53,4670.82 h60
  text "-3mil / +3mil" at 9534.08,4670.82 h60
  text "3" at 5105.32,4520.82 h60
  text "33.47mil (0.850mm)" at 5695.17,4520.82 h60
  text "PTH" at 6794.85,4520.82 h60
  text "Round" at 7300.72,4520.82 h60
  text "Top Layer - Bottom Layer" at 8034.53,4520.82 h60
  text "-3mil / +3mil" at 9534.08,4520.82 h60
  text "2" at 5105.32,4370.82 h60
  text "35.43mil (0.900mm)" at 5695.17,4370.82 h60
  text "PTH" at 6794.85,4370.82 h60
  text "Round" at 7300.72,4370.82 h60
  text "Top Layer - Bottom Layer" at 8034.53,4370.82 h60
  text "-3mil / +3mil" at 9534.08,4370.82 h60
  text "4" at 5105.32,4220.82 h60
  text "40.00mil (1.016mm)" at 5695.17,4220.82 h60
  text "PTH" at 6794.85,4220.82 h60
  text "Round" at 7300.72,4220.82 h60
  text "Top Layer - Bottom Layer" at 8034.53,4220.82 h60
  text "-3mil / +3mil" at 9534.08,4220.82 h60
  text "12" at 5105.32,4070.82 h60
  text "43.31mil (1.100mm)" at 5695.17,4070.82 h60
  text "PTH" at 6794.85,4070.82 h60
  text "Round" at 7300.72,4070.82 h60
  text "Top Layer - Bottom Layer" at 8034.53,4070.82 h60
  text "-3mil / +3mil" at 9534.08,4070.82 h60
  text "F" at 4570.36,4060.83 h66.67
  text "10" at 5105.32,3920.82 h60
  text "45.28mil (1.150mm)" at 5695.17,3920.82 h60
  text "PTH" at 6794.85,3920.82 h60
  text "Round" at 7300.72,3920.82 h60
  text "Top Layer - Bottom Layer" at 8034.53,3920.82 h60
  text "-3mil / +3mil" at 9534.08,3920.82 h60
  text "4" at 5105.32,3770.82 h60
  text "51.18mil (1.300mm)" at 5695.17,3770.82 h60
  text "PTH" at 6794.85,3770.82 h60
  text "Round" at 7300.72,3770.82 h60
  text "Top Layer - Bottom Layer" at 8034.53,3770.82 h60
  text "-3mil / +3mil" at 9534.08,3770.82 h60
  text "8" at 5105.32,3620.82 h60
  text "59.06mil (1.500mm)" at 5695.17,3620.82 h60
  text "PTH" at 6794.85,3620.82 h60
  text "Round" at 7300.72,3620.82 h60
  text "Top Layer - Bottom Layer" at 8034.53,3620.82 h60
  text "-3mil / +3mil" at 9534.08,3620.82 h60
  text "15" at 5105.32,3470.82 h60
  text "63.00mil (1.600mm)" at 5695.17,3470.82 h60
  text "PTH" at 6794.85,3470.82 h60
  text "Round" at 7300.72,3470.82 h60
  text "Top Layer - Bottom Layer" at 8034.53,3470.82 h60
  text "-3mil / +3mil" at 9534.08,3470.82 h60
  text "812 Total" at 5105.32,3320.82 h60
  text ".Layer_Name" at -36.39,-1858.41 h60
M17 Embedded Cavity:
  text ".Layer_Name" at -36.39,-1858.41 h60
M18 Embedded Assembly:
  text ".Layer_Name" at -36.39,-1858.41 h60
M19 Embedded Keepout:
  text ".Layer_Name" at -36.39,-1858.41 h60

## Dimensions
157.85,2799.97 to 157.49,-0.03 on M2 Board Dimensions
4400,2641.56 to 0,2642.49 on M2 Board Dimensions
4242.52,2641.56 to 4505,2803 on M2 Board Dimensions
-613.39,-1399.91 to 386.61,-1399.91 on M2 Board Dimensions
